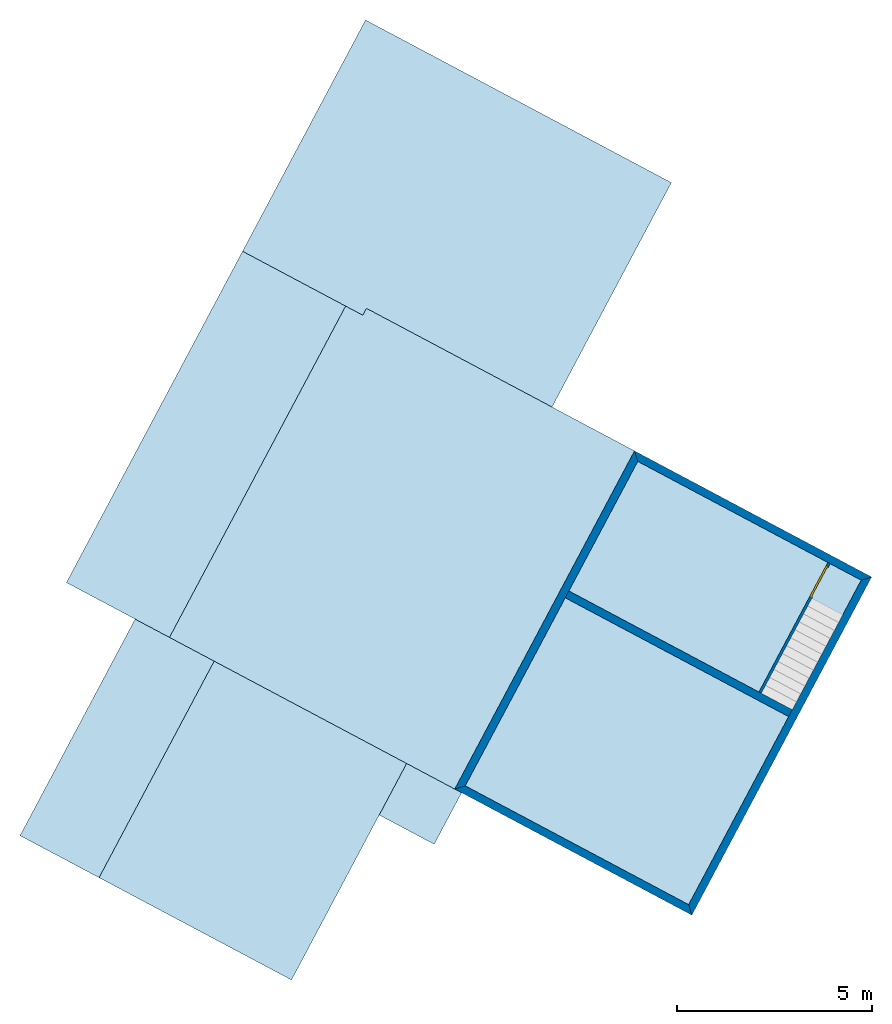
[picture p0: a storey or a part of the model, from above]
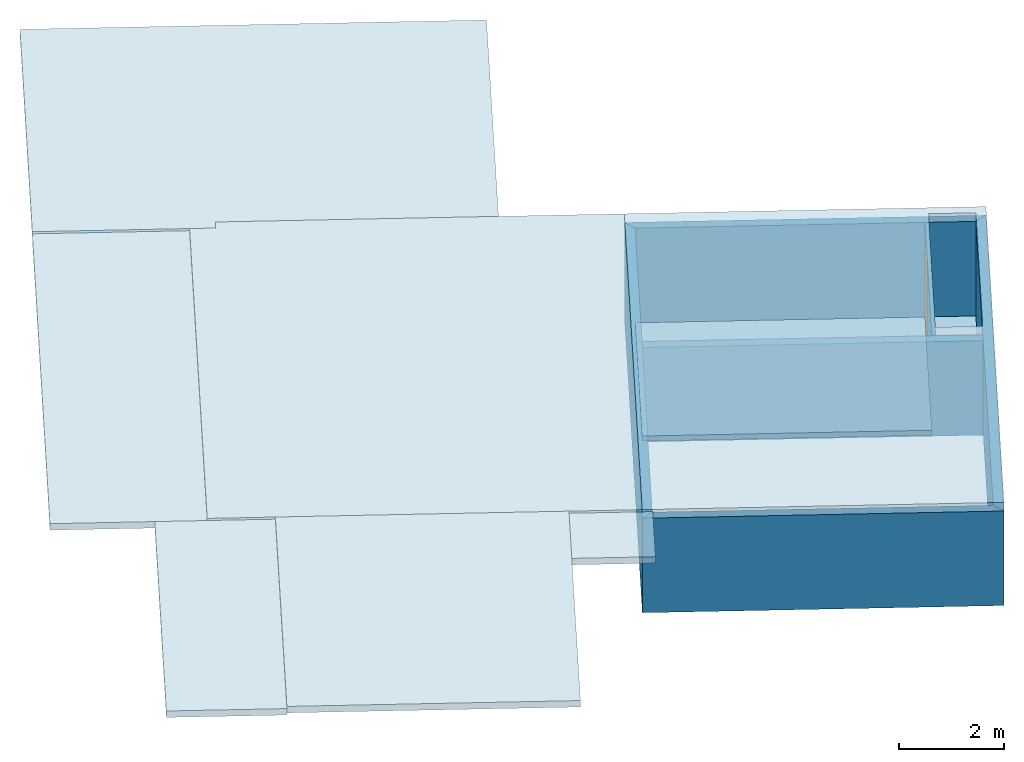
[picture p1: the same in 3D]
Properties of the parts of a building model (IFC2X3)

# File
Description: ViewDefinition [CoordinationView_V2.0], Option [Elements to export: Visible elements (on all stories)], Option [Partial Structure Display: Entire Model], Option [IFC Domain: All], Option [Structural Function: All Elements], Option [Convert Grid elements: On], Option [Convert IFC Annotations and Archicad 2D elements: Off], Option [Convert 2D symbols of Doors and Windows: Off], Option [Export geometries that Participates in Collision Detection only: Off], Option [Split complex elements: Off], Option [Material Preservation: Explode where necessary], Option [Elements in Solid Element Operations: Extruded/revolved], Option [Elements with junctions: Extruded/revolved without junctions], Option [IFC Model position: Survey Point and Project Origin], Option [Curtain Wall export mode: Container Element], Option [Railing export mode: Single Element], Option [Stair export mode: Container Element], Option [Properties To Export: All properties], Option [Space containment: Off], Option [Geometry to type objects: Off], Option [Element Properties: Off], Option [Building Material Properties: Off], Option [Element Parameters: Off], Option [Component Parameters: Off], Option [IFC Base Quantities: Off], Option [Door Window Parameters: Off], Option [IFC Space boundaries: Off], Option [Archicad Zone Categories as IFC Space classification data: Off], Option [Element Classifications: On]
File name: G:\STATION DOCUMENTS\FICHIERS COURS\BAC PRO TEBAA\BACHOTAGE\TP_ARCHICAD\01_ARCHICAD_RENOV_MUR RIDEAU\TP_MR\151009-ECHEGUT3.ifc
Time: 2024-06-17T15:18:53
Author: Architect
Organization: Building Designer Office
Written by: DDS_IFC v3.0
Made in: IFC file generated by Graphisoft Archicad 27.0.0 FRA FULL Windows version (IFC add-on version: 3001 FRA FULL).
Authorization: The authorising person

# IfcSite, Site
RefLatitude: 47, 19, 0, 0; RefLongitude: 5, 2, 0, 0; RefElevation: 0 m

# IfcBuildingStorey (3)
In: Bâtiment
Name | Elevation (m)
RDC | 0
CAVE | -2.5
toiture | 2.7

# IfcBeam: Béton 3304368070 120 x 300, Poutre-069
In: RDC
Classification: Poutre (Classification Archicad); Material: Béton 3304368070
AC_Pset_RenovationAndPhasing - Renovation Status: Existing
Pset_BeamCommon - Reference: Béton 3304368070 120 x 300

# IfcBeam: Béton 3304368070 200 x 2500 (2)
In: RDC
Classification: Poutre (Classification Archicad); Material: Béton 3304368070
AC_Pset_RenovationAndPhasing - Renovation Status: Existing
Pset_BeamCommon - Reference: Béton 3304368070 200 x 2500

# IfcBuildingElementPart (2)
In: RDC
Name | Material
Isolation 272048125 | Isolation 272048125
Maçonnerie 290464332 | Maçonnerie 290464332

# IfcBuildingElementProxy: Baignoire 16, Obj.-481
In: RDC
AC_Pset_RenovationAndPhasing - Renovation Status: Existing

# IfcBuildingElementProxy: Canapé modulable 1 27 (4)
In: RDC
AC_Pset_RenovationAndPhasing - Renovation Status: Existing

# IfcBuildingElementProxy: Chaise 10 27 (4)
In: RDC
AC_Pset_RenovationAndPhasing - Renovation Status: Existing

# IfcBuildingElementProxy: Chaudière à gaz 02 27, Obj.-484
In: RDC
AC_Pset_RenovationAndPhasing - Renovation Status: Existing

# IfcBuildingElementProxy: Cylindre 27, Obj.-482
In: toiture
AC_Pset_RenovationAndPhasing - Renovation Status: Existing

# IfcBuildingElementProxy: Cône 27, Obj.-482
In: toiture
AC_Pset_RenovationAndPhasing - Renovation Status: Existing

# IfcBuildingElementProxy: Elément bas avec plusieurs tiroirs 24, Obj.-483
In: RDC
AC_Pset_RenovationAndPhasing - Renovation Status: Existing

# IfcBuildingElementProxy: Elément bas d'angle L 24, Obj.-483
In: RDC
AC_Pset_RenovationAndPhasing - Renovation Status: Existing

# IfcBuildingElementProxy: Elément haut 24, Obj.-482
In: RDC
AC_Pset_RenovationAndPhasing - Renovation Status: Existing

# IfcBuildingElementProxy: Elément haut avec four 24, Obj.-482
In: RDC
AC_Pset_RenovationAndPhasing - Renovation Status: Existing

# IfcBuildingElementProxy: Elément simple avec trois portes 21, Obj.-483
In: RDC
AC_Pset_RenovationAndPhasing - Renovation Status: Existing

# IfcBuildingElementProxy: Elément suspendu triple 24, Obj.-483
In: RDC
AC_Pset_RenovationAndPhasing - Renovation Status: Existing

# IfcBuildingElementProxy: Evier de nettoyage 27, Obj.-483
In: RDC
AC_Pset_RenovationAndPhasing - Renovation Status: Existing

# IfcBuildingElementProxy: Familiale compacte 27, Obj.-481
In: RDC
AC_Pset_RenovationAndPhasing - Renovation Status: Existing

# IfcBuildingElementProxy: Fire Box #1560, Obj.-484
In: RDC
AC_Pset_RenovationAndPhasing - Renovation Status: Existing

# IfcBuildingElementProxy: Gouttière 27 (2)
In: toiture
AC_Pset_RenovationAndPhasing - Renovation Status: Existing

# IfcBuildingElementProxy: Hotte 27, Obj.-483
In: RDC
AC_Pset_RenovationAndPhasing - Renovation Status: Existing

# IfcBuildingElementProxy: Lave linge 27, Obj.-483
In: RDC
AC_Pset_RenovationAndPhasing - Renovation Status: Existing

# IfcBuildingElementProxy: Lave-vaisselle encastrable 27 (2)
In: RDC
AC_Pset_RenovationAndPhasing - Renovation Status: Existing

# IfcBuildingElementProxy: Lit double 02 12, Obj.-633
In: RDC
AC_Pset_RenovationAndPhasing - Renovation Status: Existing

# IfcBuildingElementProxy: Lit une personne 01 12 (2)
In: RDC
AC_Pset_RenovationAndPhasing - Renovation Status: Existing

# IfcBuildingElementProxy: Meuble à plans 27, Obj.-483
In: RDC
AC_Pset_RenovationAndPhasing - Renovation Status: Existing

# IfcBuildingElementProxy: Monospace compact 27, Obj.-481
In: RDC
AC_Pset_RenovationAndPhasing - Renovation Status: Existing

# IfcBuildingElementProxy: Panne 20 (15)
In: toiture
AC_Pset_RenovationAndPhasing - Renovation Status: Existing

# IfcBuildingElementProxy: Pompe à chaleur aérothermique 27, Obj.-483
In: RDC
AC_Pset_RenovationAndPhasing - Renovation Status: Existing

# IfcBuildingElementProxy: Réfrigérateur 2 portes 27, Obj.-482
In: RDC
AC_Pset_RenovationAndPhasing - Renovation Status: Existing

# IfcBuildingElementProxy: TV plate 27, Obj.-483
In: RDC
AC_Pset_RenovationAndPhasing - Renovation Status: Existing

# IfcBuildingElementProxy: Table de cuisson électrique 27, Obj.-484
In: RDC
AC_Pset_RenovationAndPhasing - Renovation Status: Existing

# IfcBuildingElementProxy: Table salle à manger 01 27, Obj.-483
In: RDC
AC_Pset_RenovationAndPhasing - Renovation Status: Existing

# IfcBuildingElementProxy: Tuyau descente 27 (2)
In: RDC
AC_Pset_RenovationAndPhasing - Renovation Status: Existing

# IfcBuildingElementProxy: Tuyau descente complexe 27 (2)
In: RDC
AC_Pset_RenovationAndPhasing - Renovation Status: Existing

# IfcColumn: Bloc béton 2014500447 160 x 160, Pot-040
In: RDC
Classification: Poteau (Classification Archicad); Material: Bloc béton 2014500447
AC_Pset_RenovationAndPhasing - Renovation Status: Existing
Pset_ColumnCommon - IsExternal: no; LoadBearing: yes; Reference: Bloc béton 2014500447 160 x 160

# IfcDoor: P_coul dans mur 12 (2)
In: RDC
Type - OperationType: SLIDING_TO_LEFT; ParameterTakesPrecedence: no; Sizeable: no
OverallHeight: 2 m; Classification: Porte (Classification Archicad)
Pset_DoorCommon - ThermalTransmittance: 0
AC_Pset_RenovationAndPhasing - Renovation Status: Existing
Name | OverallWidth (m)
porte 76 | 0.9
porte 76 | 0.8

# IfcDoor: P_coul dans mur 12, porte 76
In: RDC
Type - OperationType: SLIDING_TO_RIGHT; ParameterTakesPrecedence: no; Sizeable: no
OverallHeight: 2 m; OverallWidth: 0.8 m; Classification: Porte (Classification Archicad)
Pset_DoorCommon - ThermalTransmittance: 0
AC_Pset_RenovationAndPhasing - Renovation Status: Existing

# IfcDoor: P_double coul 1 10 (2)
In: RDC
Type - OperationType: SLIDING_TO_LEFT; ParameterTakesPrecedence: no; Sizeable: no
Classification: Porte (Classification Archicad)
Pset_DoorCommon - ThermalTransmittance: 0
AC_Pset_RenovationAndPhasing - Renovation Status: Existing
Name | OverallHeight (m) | OverallWidth (m)
porte 77 | 2.1 | 1.77
porte 77 | 2.5 | 1.5

# IfcDoor: P_double coul 1 10, porte 77
In: RDC
Type - OperationType: SLIDING_TO_RIGHT; ParameterTakesPrecedence: no; Sizeable: no
OverallHeight: 2.5 m; OverallWidth: 1.5 m; Classification: Porte (Classification Archicad)
Pset_DoorCommon - ThermalTransmittance: 0
AC_Pset_RenovationAndPhasing - Renovation Status: Existing

# IfcDoor: P_int simple à carreaux 10 (5)
In: RDC
Type - OperationType: SINGLE_SWING_LEFT; ParameterTakesPrecedence: no; Sizeable: no
OverallHeight: 2.09 m; Classification: Porte (Classification Archicad)
Pset_DoorCommon - ThermalTransmittance: 0
AC_Pset_RenovationAndPhasing - Renovation Status: Existing
Name | OverallWidth (m)
4 x porte 76 | 0.91
porte 77 | 1.01

# IfcDoor: P_int simple à carreaux 10 (6)
Type - OperationType: SINGLE_SWING_RIGHT; ParameterTakesPrecedence: no; Sizeable: no
OverallHeight: 2.09 m; Classification: Porte (Classification Archicad)
Pset_DoorCommon - ThermalTransmittance: 0
AC_Pset_RenovationAndPhasing - Renovation Status: Existing
Name | In | OverallWidth (m)
porte 77 | CAVE | 0.91
2 x porte 75 | RDC | 1.01
porte 76 | RDC | 0.91
porte 77 | RDC | 0.91
porte 76 | RDC | 1.01

# IfcDoor: P_métallique 10 (2)
In: RDC
Type - OperationType: SINGLE_SWING_RIGHT; ParameterTakesPrecedence: no; Sizeable: no
OverallHeight: 2.15 m; Classification: Porte (Classification Archicad)
Pset_DoorCommon - ThermalTransmittance: 0
AC_Pset_RenovationAndPhasing - Renovation Status: Existing
Name | OverallWidth (m)
porte 75 | 0.9
porte 75 | 1

# IfcDoor: Porte coulissante avec imposte 27, porte 77
In: RDC
Type - OperationType: USERDEFINED; ParameterTakesPrecedence: no; Sizeable: no
OverallHeight: 3 m; OverallWidth: 4.5 m; Classification: Porte (Classification Archicad)
Pset_DoorCommon - ThermalTransmittance: 0
AC_Pset_RenovationAndPhasing - Renovation Status: Existing

# IfcSlab: Hachure vide 3286431593 120 (3)
In: CAVE
Type - PredefinedType: FLOOR
Classification: Dalle (Classification Archicad); Material: Hachure vide 3286431593 0.12 m
AC_Pset_RenovationAndPhasing - Renovation Status: Existing

# IfcSlab: Hachure vide 3286431593 15 (4)
In: toiture
Type - PredefinedType: FLOOR
Classification: Dalle (Classification Archicad); Material: Hachure vide 3286431593 0.015 m
AC_Pset_RenovationAndPhasing - Renovation Status: Existing

# IfcSlab: Hachure vide 3286431593 150 (7)
Type - PredefinedType: FLOOR
Classification: Dalle (Classification Archicad); Material: Hachure vide 3286431593 0.15 m
AC_Pset_RenovationAndPhasing - Renovation Status: Existing
Name | In
6 x terre plein | CAVE
terre plein | RDC

# IfcSlab: Hachure vide 3286431593 200, terre plein
In: CAVE
Type - PredefinedType: FLOOR
Classification: Dalle (Classification Archicad); Material: Hachure vide 3286431593 0.2 m
AC_Pset_RenovationAndPhasing - Renovation Status: Existing

# IfcSlab: Isolation 288766638 200, terre plein
In: toiture
Type - PredefinedType: FLOOR
Classification: Dalle (Classification Archicad); Material: Isolation 288766638 0.2 m
AC_Pset_RenovationAndPhasing - Renovation Status: Existing

# IfcSlab: Isolation 288766638 50, terre plein
In: toiture
Type - PredefinedType: FLOOR
Classification: Dalle (Classification Archicad); Material: Isolation 288766638 0.05 m
AC_Pset_RenovationAndPhasing - Renovation Status: Existing

# IfcSlab: Lame d'air 3030760239 15, Tpan-09
In: toiture
Type - PredefinedType: ROOF
Classification: Toit (Classification Archicad); Material: Lame d'air 3030760239 0.0149522 m
AC_Pset_RenovationAndPhasing - Renovation Status: Existing

# IfcSlab: Lame d'air 3030760239 200 (4)
In: toiture
Type - PredefinedType: ROOF
Classification: Toit (Classification Archicad)
AC_Pset_RenovationAndPhasing - Renovation Status: Existing
Name | Material
3 x Tpan-09 | Lame d'air 3030760239 0.2 m
Tpan-09 | Lame d'air 3030760239 0.20036 m

# IfcStair, Stair-013
In: CAVE
Classification: Escalier (Classification Archicad)
AC_Pset_RenovationAndPhasing - Renovation Status: Existing
Pset_StairCommon - IsExternal: no

# IfcWall: CLOISON 7 0024849982 70, Mur-396
In: toiture
Classification: Mur (Classification Archicad); Material: Isolation 269295175
AC_Pset_RenovationAndPhasing - Renovation Status: Existing

# IfcWall: MUR EXT 34 0024849982 340, Mur-393
In: RDC
Classification: Mur (Classification Archicad)
AC_Pset_RenovationAndPhasing - Renovation Status: Existing

# IfcWallStandardCase: CLOISON 10 100 (3)
In: RDC
Classification: Mur (Classification Archicad); Material: Isolation 269295175 0.1 m
AC_Pset_RenovationAndPhasing - Renovation Status: Existing
Name
Mur-394
2 x Mur-396

# IfcWallStandardCase: CLOISON 15 150, Mur-397
In: RDC
Classification: Mur (Classification Archicad); Material: Isolation 269295175 0.15 m
AC_Pset_RenovationAndPhasing - Renovation Status: Existing

# IfcWallStandardCase: CLOISON 2 0024849982 20, Mur-395
In: RDC
Classification: Mur (Classification Archicad); Material: Isolation 269295175 0.02 m
AC_Pset_RenovationAndPhasing - Renovation Status: Existing

# IfcWallStandardCase: CLOISON 7 0024849982 70 (26)
Classification: Mur (Classification Archicad); Material: Isolation 269295175 0.07 m
AC_Pset_RenovationAndPhasing - Renovation Status: Existing
Name | In
9 x Mur-395 | RDC
11 x Mur-396 | RDC
4 x Mur-394 | RDC
Mur-397 | RDC
Mur-396 | toiture

# IfcWallStandardCase: CLOISON 7 70, Mur-396
In: CAVE
Classification: Mur (Classification Archicad); Material: Isolation 269295175 0.07 m
AC_Pset_RenovationAndPhasing - Renovation Status: Existing

# IfcWallStandardCase: CLOISON PLACOSTYL 13 0024849982 130 (2)
In: RDC
Classification: Mur (Classification Archicad); Material: Isolation 272048125 0.01 m, Bloc béton 288373292 0.11 m, Isolation 272048125 0.01 m
AC_Pset_RenovationAndPhasing - Renovation Status: Existing
Name
Mur-398
Mur-397

# IfcWallStandardCase: MUR EXT 20 0024849982 200 (4)
In: RDC
Classification: Mur (Classification Archicad); Material: Maçonnerie 290464332 0.2 m
AC_Pset_RenovationAndPhasing - Renovation Status: Existing
Name
Mur-395
Mur-394
2 x Mur-393

# IfcWallStandardCase: MUR EXT 20 200 (5)
In: CAVE
Classification: Mur (Classification Archicad); Material: Maçonnerie 290464332 0.2 m
AC_Pset_RenovationAndPhasing - Renovation Status: Existing
Name
Mur-399
Mur-398
2 x Mur-396
Mur-397

# IfcWallStandardCase: MUR EXT 34 0024849982 340 (11)
In: RDC
Classification: Mur (Classification Archicad); Material: Maçonnerie 290464332 0.2 m, Isolation 272048125 0.14 m
AC_Pset_RenovationAndPhasing - Renovation Status: Existing
Name
2 x Mur-394
2 x Mur-391
2 x Mur-395
2 x Mur-393
2 x Mur-390
Mur-396

# IfcWallStandardCase: MUR EXT 34 340, Mur-392
In: RDC
Classification: Mur (Classification Archicad); Material: Maçonnerie 290464332 0.2 m, Isolation 272048125 0.14 m
AC_Pset_RenovationAndPhasing - Renovation Status: Existing

# IfcWindow: Fen châssis simple 10 (7)
In: RDC
Type - OperationType: SINGLE_PANEL; ParameterTakesPrecedence: no; Sizeable: no
Classification: Fenêtre (Classification Archicad)
Pset_WindowCommon - ThermalTransmittance: 0
Pset_ManufacturerOccurrence - SerialNumber: Sans
AC_Pset_RenovationAndPhasing - Renovation Status: Existing
Name | OverallHeight (m) | OverallWidth (m)
Fen-157 | 0.75 | 1.8
Fen-157 | 0.75 | 0.5
Fen-158 | 0.95 | 0.6
Fen-156 | 0.75 | 0.5
2 x Fen-157 | 0.6 | 1.4
Fen-155 | 3 | 0.8

# IfcWindow: Fen à carreaux 10 (9)
In: RDC
Type - OperationType: SINGLE_PANEL; ParameterTakesPrecedence: no; Sizeable: no
Classification: Fenêtre (Classification Archicad)
Pset_WindowCommon - ThermalTransmittance: 0
AC_Pset_RenovationAndPhasing - Renovation Status: Existing
Name | OverallHeight (m) | OverallWidth (m)
3 x Fen-156 | 1.9 | 0.6
3 x Fen-155 | 2.15 | 0.9
3 x Fen-156 | 2.15 | 0.9
